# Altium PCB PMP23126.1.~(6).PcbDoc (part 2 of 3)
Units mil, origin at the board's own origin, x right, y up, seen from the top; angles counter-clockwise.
Board outline 1315.03 x 1390.8 mil, 6 copper layers (Top Layer, MidLayer1, MidLayer2, MidLayer3, MidLayer4, Bottom Layer), stack 72.6 mil thick; 49 components, 55 nets, 222 pads, 193 vias.
Unrouted connection lines stored in the file: 15.

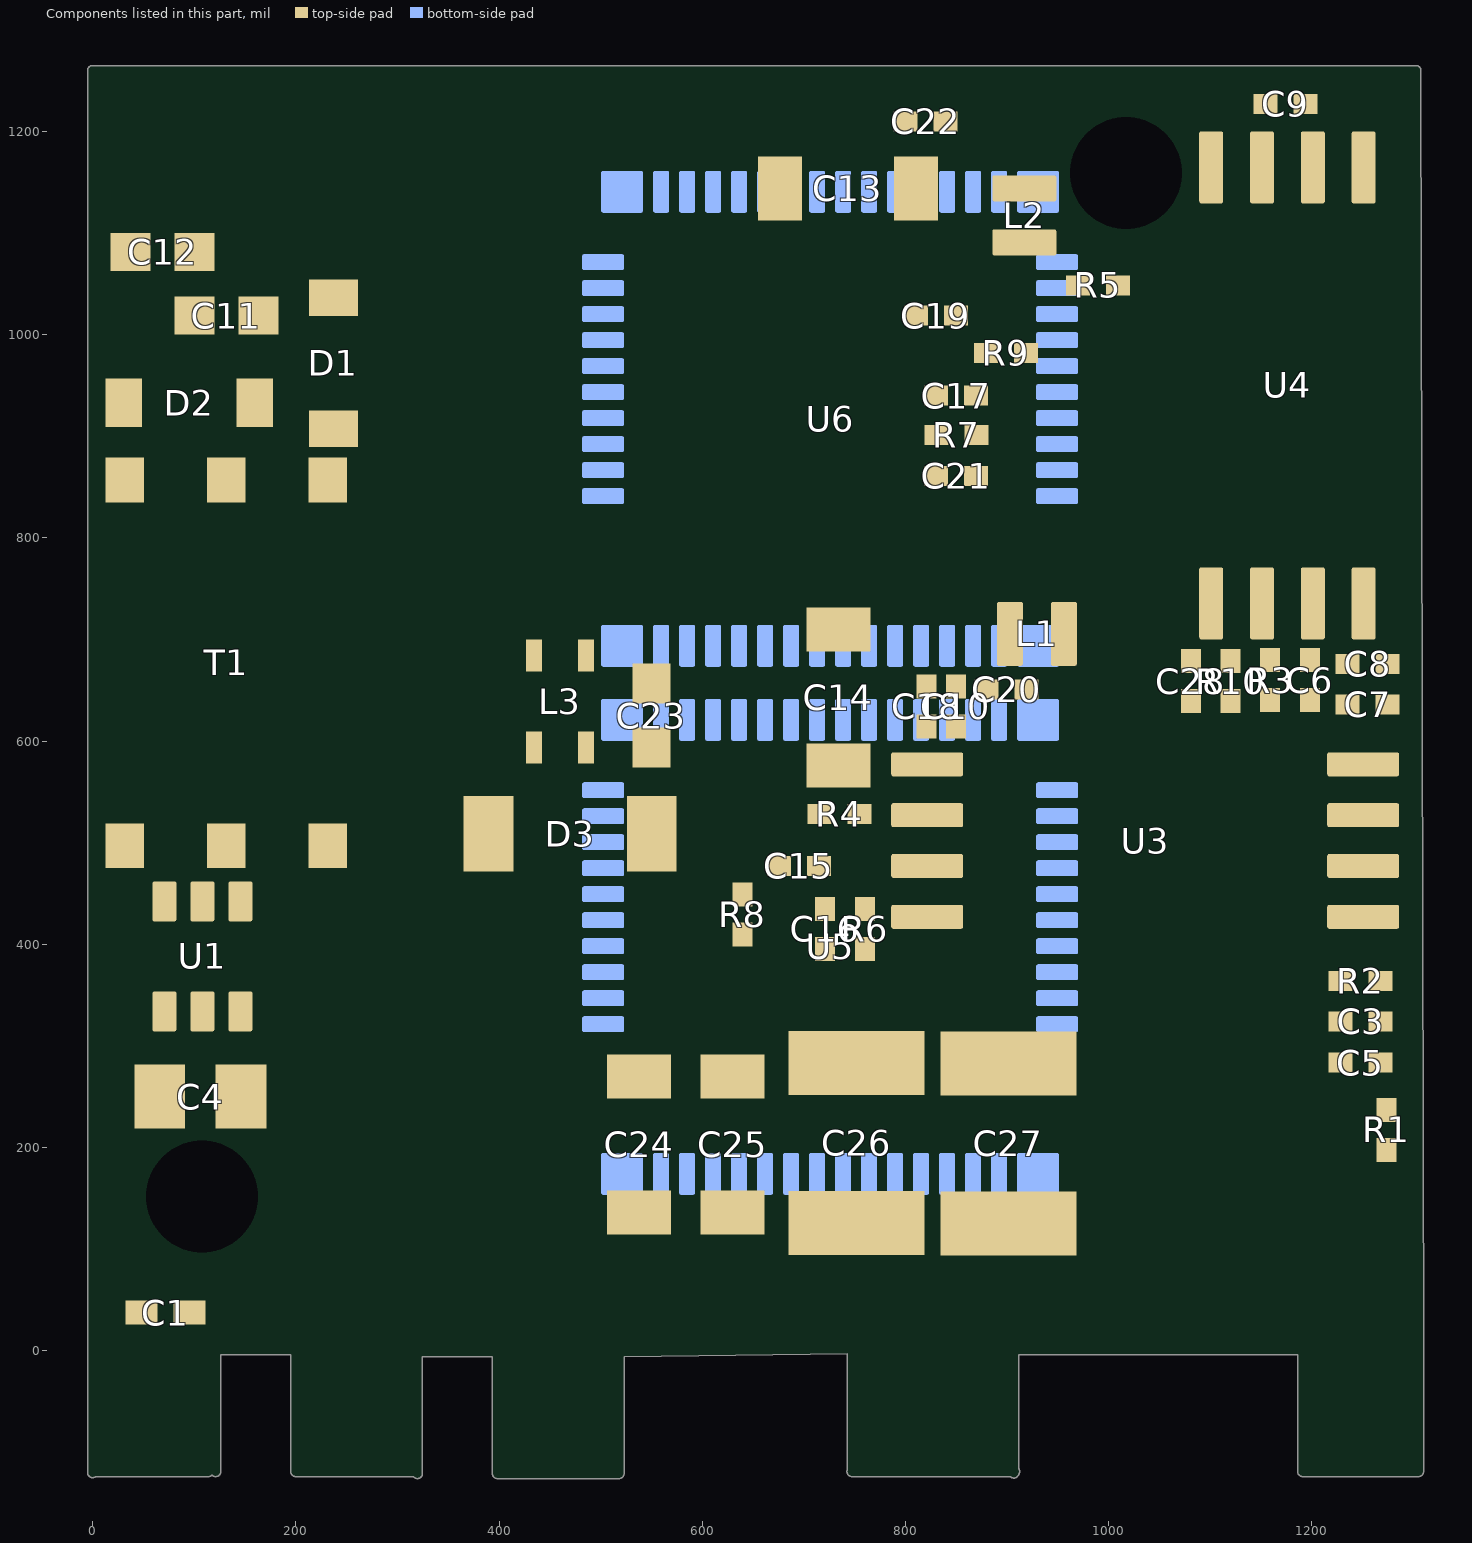
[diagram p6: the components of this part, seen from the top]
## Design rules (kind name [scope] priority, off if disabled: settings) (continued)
PolygonConnect PolygonConnect_45 [All vs IsNamedPolygon('Vbulk1') Or  IsNamedPolygon('TOP_LAYER_VBULK_P104') Or  IsNamedPolygon('SIGNAL_LAYER_1_VBULK1_P106') Or  IsNamedPolygon('Iout_SNS') Or  IsNamedPolygon('SIGNAL_LAYER_2_VBB_P094') Or  IsNamedPolygon('Line') Or  IsNamedPolygon('T200_4') Or  IsNamedPolygon('ZCD') Or  IsNamedPolygon('C108_1') Or  IsNamedPolygon('PGND') Or  IsNamedPolygon('BOTTOM_LAYER_NETC106_2_P030') Or  IsNamedPolygon('5Vp') Or  IsNamedPolygon('C108_1') Or  IsNamedPolygon('Line') Or  IsNamedPolygon('C102_1') Or  IsNamedPolygon('T200_4') Or  IsNamedPolygon('12Vp') Or  IsNamedPolygon('D403_2') Or  IsNamedPolygon('T200_6') Or  IsNamedPolygon('TOP_LAYER_54V1_P046') Or  IsNamedPolygon('TOP_LAYER_54V2_P048') Or  IsNamedPolygon('C108_1') Or  IsNamedPolygon('C108_1') Or  IsNamedPolygon('SWNODE3') Or  IsNamedPolygon('TOP_LAYER_54V2_P048') Or  IsNamedPolygon('PGND') Or  IsNamedPolygon('D403_2') Or  IsNamedPolygon('C108_1') Or  IsNamedPolygon('C108_1') Or  IsNamedPolygon('T200_6') Or  IsNamedPolygon('SGND') Or  IsNamedPolygon('SWNODE') Or  IsNamedPolygon('SGND') Or  IsNamedPolygon('SWNODE3') Or  IsNamedPolygon('BOTTOM_LAYER_54V1_P128') Or  IsNamedPolygon('C102_1') Or  IsNamedPolygon('SWNODE4') Or  IsNamedPolygon('C102_1') Or  IsNamedPolygon('SGND') Or  IsNamedPolygon('C102_1') Or  IsNamedPolygon('SGND') Or  IsNamedPolygon('VSR') Or  IsNamedPolygon('SGND') Or  IsNamedPolygon('SGND') Or  IsNamedPolygon('VSR') Or  IsNamedPolygon('SGND') Or  IsNamedPolygon('SWNODE4') Or  IsNamedPolygon('SGND') Or  IsNamedPolygon('SGND') Or  IsNamedPolygon('Vbulk1') Or  IsNamedPolygon('SGND') Or  IsNamedPolygon('PGND') Or  IsNamedPolygon('SGND') Or  IsNamedPolygon('PGND') Or  IsNamedPolygon('SWNODE3') Or  IsNamedPolygon('ZCD') Or  IsNamedPolygon('VSR') Or  IsNamedPolygon('C102_1') Or  IsNamedPolygon('SWNODE4') Or  IsNamedPolygon('C102_1') Or  IsNamedPolygon('SWNODE4') Or  IsNamedPolygon('SWNODE3') Or  IsNamedPolygon('PGND') Or  IsNamedPolygon('SGND') Or  IsNamedPolygon('D400_2') Or  IsNamedPolygon('SGND') Or  IsNamedPolygon('5Vs') Or  IsNamedPolygon('VBB') Or  IsNamedPolygon('T200_4') Or  IsNamedPolygon('T200_6') Or  IsNamedPolygon('SWNODE4') Or  IsNamedPolygon('LEG4_HS_DRV') Or  IsNamedPolygon('LEG4_LS_DRV') Or  IsNamedPolygon('LEG3_HS_DRV') Or  IsNamedPolygon('BOTTOM_LAYER_54V1_P128') Or  IsNamedPolygon('TOP_LAYER_12VS_P126') Or  IsNamedPolygon('Iout_SNS') Or  IsNamedPolygon('SWNODE3') Or  IsNamedPolygon('SWNODE3') Or  IsNamedPolygon('SWNODE3') Or  IsNamedPolygon('VBB') Or  IsNamedPolygon('Line') Or  IsNamedPolygon('D404_2') Or  IsNamedPolygon('SGND') Or  IsNamedPolygon('VBB') Or  IsNamedPolygon('VBB') Or  IsNamedPolygon('PGND') Or  IsNamedPolygon('PGND') Or  IsNamedPolygon('PGND') Or  IsNamedPolygon('PGND') Or  IsNamedPolygon('PGND') Or  IsNamedPolygon('ZCD') Or  IsNamedPolygon('ZCD') Or  IsNamedPolygon('C412_2') Or  IsNamedPolygon('VBB') Or  IsNamedPolygon('PGND') Or  IsNamedPolygon('PGND') Or  IsNamedPolygon('PGND') Or  IsNamedPolygon('PGND') Or  IsNamedPolygon('PGND') Or  IsNamedPolygon('PGND') Or  IsNamedPolygon('PGND') Or  IsNamedPolygon('VBB') Or  IsNamedPolygon('D404_2') Or  IsNamedPolygon('VBB') Or  IsNamedPolygon('Vbulk1') Or  IsNamedPolygon('Vbulk1') Or  IsNamedPolygon('ZCD') Or  IsNamedPolygon('Neutral') Or  IsNamedPolygon('Neutral') Or  IsNamedPolygon('C106_2') Or  IsNamedPolygon('C106_2') Or  IsNamedPolygon('C106_2') Or  IsNamedPolygon('SWNODE') Or  IsNamedPolygon('Vbulk1') Or  IsNamedPolygon('Earth1') Or  IsNamedPolygon('Earth1') Or  IsNamedPolygon('Earth1') Or  IsNamedPolygon('Earth1') Or  IsNamedPolygon('Earth1') Or  IsNamedPolygon('Earth1') Or  IsNamedPolygon('ZCD') Or  IsNamedPolygon('VBB') Or  IsNamedPolygon('PGND') Or  IsNamedPolygon('D106_1') Or  IsNamedPolygon('PGND') Or  IsNamedPolygon('PGND') Or  IsNamedPolygon('D106_1') Or  IsNamedPolygon('VBB') Or  IsNamedPolygon('D106_1') Or  IsNamedPolygon('PGND')] p15: connectstyle=Direct reliefconductorwidth=10 reliefentries=4 polygonreliefangle="90 Angle" airgapwidth=10
PolygonConnect PolygonConnect_44 [All vs IsNamedPolygon('Earth1') Or  IsNamedPolygon('Vbulk1') Or  IsNamedPolygon('Vbulk1') Or  IsNamedPolygon('VBB') Or  IsNamedPolygon('Vbulk1') Or  IsNamedPolygon('ZCD') Or  IsNamedPolygon('VBB') Or  IsNamedPolygon('PGND') Or  IsNamedPolygon('C412_2') Or  IsNamedPolygon('ZCD') Or  IsNamedPolygon('D106_1') Or  IsNamedPolygon('D106_1') Or  IsNamedPolygon('ZCD') Or  IsNamedPolygon('PGND') Or  IsNamedPolygon('PGND') Or  IsNamedPolygon('ZCD') Or  IsNamedPolygon('VBB') Or  IsNamedPolygon('PGND') Or  IsNamedPolygon('VBB') Or  IsNamedPolygon('PGND') Or  IsNamedPolygon('D106_1') Or  IsNamedPolygon('PGND') Or  IsNamedPolygon('PGND') Or  IsNamedPolygon('PGND') Or  IsNamedPolygon('VBB') Or  IsNamedPolygon('PGND') Or  IsNamedPolygon('PGND') Or  IsNamedPolygon('C102_1') Or  IsNamedPolygon('ZCD') Or  IsNamedPolygon('C102_1') Or  IsNamedPolygon('C102_1') Or  IsNamedPolygon('C102_1') Or  IsNamedPolygon('PGND') Or  IsNamedPolygon('C102_1') Or  IsNamedPolygon('Line') Or  IsNamedPolygon('T200_4') Or  IsNamedPolygon('T200_4') Or  IsNamedPolygon('SIGNAL_LAYER_1_VBULK1_P106') Or  IsNamedPolygon('TOP_LAYER_VBULK_P104') Or  IsNamedPolygon('T200_4') Or  IsNamedPolygon('SGND') Or  IsNamedPolygon('T200_6') Or  IsNamedPolygon('C108_1') Or  IsNamedPolygon('SWNODE3') Or  IsNamedPolygon('SWNODE') Or  IsNamedPolygon('SWNODE3') Or  IsNamedPolygon('LEG3_HS_DRV') Or  IsNamedPolygon('BOTTOM_LAYER_NETC106_2_P030') Or  IsNamedPolygon('C102_1') Or  IsNamedPolygon('SWNODE4') Or  IsNamedPolygon('SIGNAL_LAYER_2_VBB_P094') Or  IsNamedPolygon('SGND') Or  IsNamedPolygon('VSR') Or  IsNamedPolygon('C108_1') Or  IsNamedPolygon('BOTTOM_LAYER_54V1_P128') Or  IsNamedPolygon('TOP_LAYER_54V2_P048') Or  IsNamedPolygon('TOP_LAYER_54V1_P046') Or  IsNamedPolygon('C108_1') Or  IsNamedPolygon('D403_2') Or  IsNamedPolygon('ZCD') Or  IsNamedPolygon('PGND') Or  IsNamedPolygon('SWNODE3') Or  IsNamedPolygon('Line') Or  IsNamedPolygon('D400_2') Or  IsNamedPolygon('SGND') Or  IsNamedPolygon('PGND') Or  IsNamedPolygon('SGND') Or  IsNamedPolygon('LEG4_HS_DRV') Or  IsNamedPolygon('SWNODE3') Or  IsNamedPolygon('5Vs') Or  IsNamedPolygon('SWNODE4') Or  IsNamedPolygon('SGND') Or  IsNamedPolygon('SGND') Or  IsNamedPolygon('C108_1') Or  IsNamedPolygon('5Vp') Or  IsNamedPolygon('12Vp') Or  IsNamedPolygon('Iout_SNS') Or  IsNamedPolygon('D404_2') Or  IsNamedPolygon('SGND') Or  IsNamedPolygon('T200_6') Or  IsNamedPolygon('TOP_LAYER_54V2_P048') Or  IsNamedPolygon('SGND') Or  IsNamedPolygon('SWNODE3') Or  IsNamedPolygon('SWNODE4') Or  IsNamedPolygon('Iout_SNS') Or  IsNamedPolygon('C108_1') Or  IsNamedPolygon('BOTTOM_LAYER_54V1_P128') Or  IsNamedPolygon('SWNODE3') Or  IsNamedPolygon('LEG4_LS_DRV') Or  IsNamedPolygon('SGND') Or  IsNamedPolygon('SWNODE4') Or  IsNamedPolygon('T200_6') Or  IsNamedPolygon('TOP_LAYER_12VS_P126') Or  IsNamedPolygon('Line') Or  IsNamedPolygon('Vbulk1') Or  IsNamedPolygon('SWNODE3') Or  IsNamedPolygon('SGND') Or  IsNamedPolygon('VBB') Or  IsNamedPolygon('SGND') Or  IsNamedPolygon('SGND') Or  IsNamedPolygon('SWNODE4') Or  IsNamedPolygon('PGND') Or  IsNamedPolygon('D403_2') Or  IsNamedPolygon('VSR') Or  IsNamedPolygon('SGND') Or  IsNamedPolygon('SGND') Or  IsNamedPolygon('VBB') Or  IsNamedPolygon('C108_1') Or  IsNamedPolygon('Earth1') Or  IsNamedPolygon('Earth1') Or  IsNamedPolygon('VSR') Or  IsNamedPolygon('C106_2') Or  IsNamedPolygon('Vbulk1') Or  IsNamedPolygon('C106_2') Or  IsNamedPolygon('C106_2') Or  IsNamedPolygon('Earth1') Or  IsNamedPolygon('SWNODE') Or  IsNamedPolygon('Neutral') Or  IsNamedPolygon('Earth1') Or  IsNamedPolygon('Earth1') Or  IsNamedPolygon('Neutral')] p16: connectstyle=Direct reliefconductorwidth=10 reliefentries=4 polygonreliefangle="90 Angle" airgapwidth=10
PolygonConnect PolygonConnect_43 [All vs IsNamedPolygon('SWNODE') Or  IsNamedPolygon('D403_2') Or  IsNamedPolygon('D403_2') Or  IsNamedPolygon('PGND') Or  IsNamedPolygon('BOTTOM_LAYER_NETC106_2_P030') Or  IsNamedPolygon('C102_1') Or  IsNamedPolygon('SGND') Or  IsNamedPolygon('TOP_LAYER_54V1_P046') Or  IsNamedPolygon('TOP_LAYER_54V2_P048') Or  IsNamedPolygon('TOP_LAYER_54V2_P048') Or  IsNamedPolygon('C108_1') Or  IsNamedPolygon('C108_1') Or  IsNamedPolygon('C108_1') Or  IsNamedPolygon('C108_1') Or  IsNamedPolygon('C108_1') Or  IsNamedPolygon('C108_1') Or  IsNamedPolygon('PGND') Or  IsNamedPolygon('ZCD') Or  IsNamedPolygon('Line') Or  IsNamedPolygon('5Vp') Or  IsNamedPolygon('12Vp') Or  IsNamedPolygon('T200_4') Or  IsNamedPolygon('T200_6') Or  IsNamedPolygon('SWNODE3') Or  IsNamedPolygon('T200_4') Or  IsNamedPolygon('T200_6') Or  IsNamedPolygon('SWNODE4') Or  IsNamedPolygon('VSR') Or  IsNamedPolygon('Iout_SNS') Or  IsNamedPolygon('SIGNAL_LAYER_2_VBB_P094') Or  IsNamedPolygon('Vbulk1') Or  IsNamedPolygon('TOP_LAYER_VBULK_P104') Or  IsNamedPolygon('SIGNAL_LAYER_1_VBULK1_P106') Or  IsNamedPolygon('Line') Or  IsNamedPolygon('Line') Or  IsNamedPolygon('D404_2') Or  IsNamedPolygon('VBB') Or  IsNamedPolygon('D400_2') Or  IsNamedPolygon('SGND') Or  IsNamedPolygon('PGND') Or  IsNamedPolygon('TOP_LAYER_12VS_P126') Or  IsNamedPolygon('BOTTOM_LAYER_54V1_P128') Or  IsNamedPolygon('LEG3_HS_DRV') Or  IsNamedPolygon('LEG4_LS_DRV') Or  IsNamedPolygon('LEG4_HS_DRV') Or  IsNamedPolygon('SWNODE4') Or  IsNamedPolygon('SWNODE3') Or  IsNamedPolygon('T200_6') Or  IsNamedPolygon('T200_4') Or  IsNamedPolygon('VBB') Or  IsNamedPolygon('5Vs') Or  IsNamedPolygon('SGND') Or  IsNamedPolygon('Iout_SNS') Or  IsNamedPolygon('SGND') Or  IsNamedPolygon('SWNODE3') Or  IsNamedPolygon('SWNODE3') Or  IsNamedPolygon('SWNODE3') Or  IsNamedPolygon('SWNODE3') Or  IsNamedPolygon('SGND') Or  IsNamedPolygon('SGND') Or  IsNamedPolygon('SGND') Or  IsNamedPolygon('SWNODE4') Or  IsNamedPolygon('SWNODE4') Or  IsNamedPolygon('SWNODE4') Or  IsNamedPolygon('VSR') Or  IsNamedPolygon('SWNODE3') Or  IsNamedPolygon('SGND') Or  IsNamedPolygon('SGND') Or  IsNamedPolygon('SGND') Or  IsNamedPolygon('SGND') Or  IsNamedPolygon('SGND') Or  IsNamedPolygon('SGND') Or  IsNamedPolygon('BOTTOM_LAYER_54V1_P128') Or  IsNamedPolygon('SGND') Or  IsNamedPolygon('VSR') Or  IsNamedPolygon('C102_1') Or  IsNamedPolygon('C102_1') Or  IsNamedPolygon('C102_1') Or  IsNamedPolygon('C102_1') Or  IsNamedPolygon('C102_1') Or  IsNamedPolygon('ZCD') Or  IsNamedPolygon('PGND') Or  IsNamedPolygon('PGND') Or  IsNamedPolygon('Vbulk1') Or  IsNamedPolygon('VBB') Or  IsNamedPolygon('Vbulk1') Or  IsNamedPolygon('Vbulk1') Or  IsNamedPolygon('ZCD') Or  IsNamedPolygon('Neutral') Or  IsNamedPolygon('Neutral') Or  IsNamedPolygon('C106_2') Or  IsNamedPolygon('C106_2') Or  IsNamedPolygon('C106_2') Or  IsNamedPolygon('SWNODE') Or  IsNamedPolygon('Vbulk1') Or  IsNamedPolygon('Earth1') Or  IsNamedPolygon('Earth1') Or  IsNamedPolygon('Earth1') Or  IsNamedPolygon('Earth1') Or  IsNamedPolygon('Earth1') Or  IsNamedPolygon('Earth1') Or  IsNamedPolygon('ZCD') Or  IsNamedPolygon('VBB') Or  IsNamedPolygon('PGND') Or  IsNamedPolygon('D106_1') Or  IsNamedPolygon('PGND') Or  IsNamedPolygon('PGND') Or  IsNamedPolygon('D106_1') Or  IsNamedPolygon('VBB') Or  IsNamedPolygon('D106_1') Or  IsNamedPolygon('PGND') Or  IsNamedPolygon('VBB') Or  IsNamedPolygon('VBB') Or  IsNamedPolygon('PGND') Or  IsNamedPolygon('PGND') Or  IsNamedPolygon('PGND') Or  IsNamedPolygon('PGND') Or  IsNamedPolygon('PGND')] p17: connectstyle=Direct reliefconductorwidth=10 reliefentries=4 polygonreliefangle="90 Angle" airgapwidth=10
PolygonConnect PolygonConnect_42 [All vs IsNamedPolygon('Neutral') Or  IsNamedPolygon('Earth1') Or  IsNamedPolygon('Earth1') Or  IsNamedPolygon('D404_2') Or  IsNamedPolygon('Line') Or  IsNamedPolygon('SIGNAL_LAYER_1_VBULK1_P106') Or  IsNamedPolygon('Line') Or  IsNamedPolygon('C102_1') Or  IsNamedPolygon('SWNODE3') Or  IsNamedPolygon('SWNODE3') Or  IsNamedPolygon('SWNODE') Or  IsNamedPolygon('5Vp') Or  IsNamedPolygon('T200_6') Or  IsNamedPolygon('SWNODE3') Or  IsNamedPolygon('SGND') Or  IsNamedPolygon('SWNODE3') Or  IsNamedPolygon('VSR') Or  IsNamedPolygon('C108_1') Or  IsNamedPolygon('SWNODE3') Or  IsNamedPolygon('TOP_LAYER_12VS_P126') Or  IsNamedPolygon('SGND') Or  IsNamedPolygon('SGND') Or  IsNamedPolygon('SGND') Or  IsNamedPolygon('T200_6') Or  IsNamedPolygon('SWNODE4') Or  IsNamedPolygon('C108_1') Or  IsNamedPolygon('C106_2') Or  IsNamedPolygon('SGND') Or  IsNamedPolygon('Neutral') Or  IsNamedPolygon('SIGNAL_LAYER_2_VBB_P094') Or  IsNamedPolygon('Vbulk1') Or  IsNamedPolygon('SGND') Or  IsNamedPolygon('SGND') Or  IsNamedPolygon('TOP_LAYER_54V1_P046') Or  IsNamedPolygon('TOP_LAYER_54V2_P048') Or  IsNamedPolygon('TOP_LAYER_54V2_P048') Or  IsNamedPolygon('C102_1') Or  IsNamedPolygon('SGND') Or  IsNamedPolygon('T200_4') Or  IsNamedPolygon('12Vp') Or  IsNamedPolygon('SGND') Or  IsNamedPolygon('D400_2') Or  IsNamedPolygon('LEG3_HS_DRV') Or  IsNamedPolygon('LEG4_LS_DRV') Or  IsNamedPolygon('T200_4') Or  IsNamedPolygon('BOTTOM_LAYER_54V1_P128') Or  IsNamedPolygon('SGND') Or  IsNamedPolygon('VBB') Or  IsNamedPolygon('SWNODE4') Or  IsNamedPolygon('SWNODE4') Or  IsNamedPolygon('SWNODE4') Or  IsNamedPolygon('VSR') Or  IsNamedPolygon('Iout_SNS') Or  IsNamedPolygon('VBB') Or  IsNamedPolygon('PGND') Or  IsNamedPolygon('Line') Or  IsNamedPolygon('ZCD') Or  IsNamedPolygon('D403_2') Or  IsNamedPolygon('SWNODE3') Or  IsNamedPolygon('Vbulk1') Or  IsNamedPolygon('ZCD') Or  IsNamedPolygon('LEG4_HS_DRV') Or  IsNamedPolygon('BOTTOM_LAYER_54V1_P128') Or  IsNamedPolygon('VBB') Or  IsNamedPolygon('PGND') Or  IsNamedPolygon('ZCD') Or  IsNamedPolygon('ZCD') Or  IsNamedPolygon('Earth1') Or  IsNamedPolygon('VBB') Or  IsNamedPolygon('PGND') Or  IsNamedPolygon('PGND') Or  IsNamedPolygon('Vbulk1') Or  IsNamedPolygon('SWNODE') Or  IsNamedPolygon('C106_2') Or  IsNamedPolygon('C106_2') Or  IsNamedPolygon('C108_1') Or  IsNamedPolygon('SWNODE3') Or  IsNamedPolygon('SWNODE4') Or  IsNamedPolygon('Vbulk1') Or  IsNamedPolygon('SGND') Or  IsNamedPolygon('C102_1') Or  IsNamedPolygon('BOTTOM_LAYER_NETC106_2_P030') Or  IsNamedPolygon('Earth1') Or  IsNamedPolygon('Earth1') Or  IsNamedPolygon('Vbulk1') Or  IsNamedPolygon('Earth1') Or  IsNamedPolygon('T200_6') Or  IsNamedPolygon('T200_4') Or  IsNamedPolygon('C102_1') Or  IsNamedPolygon('C102_1') Or  IsNamedPolygon('C102_1') Or  IsNamedPolygon('VBB') Or  IsNamedPolygon('5Vs') Or  IsNamedPolygon('SGND') Or  IsNamedPolygon('Iout_SNS') Or  IsNamedPolygon('C108_1') Or  IsNamedPolygon('C108_1') Or  IsNamedPolygon('C108_1') Or  IsNamedPolygon('PGND') Or  IsNamedPolygon('D403_2') Or  IsNamedPolygon('PGND') Or  IsNamedPolygon('SGND') Or  IsNamedPolygon('SGND') Or  IsNamedPolygon('VSR')] p18: connectstyle=Direct reliefconductorwidth=10 reliefentries=4 polygonreliefangle="90 Angle" airgapwidth=10
PolygonConnect PolygonConnect_41 [All vs IsNamedPolygon('VBB') Or  IsNamedPolygon('SWNODE3') Or  IsNamedPolygon('T200_4') Or  IsNamedPolygon('Earth1') Or  IsNamedPolygon('BOTTOM_LAYER_54V1_P128') Or  IsNamedPolygon('SGND') Or  IsNamedPolygon('TOP_LAYER_12VS_P126') Or  IsNamedPolygon('C102_1') Or  IsNamedPolygon('VSR') Or  IsNamedPolygon('Earth1') Or  IsNamedPolygon('Neutral') Or  IsNamedPolygon('Vbulk1') Or  IsNamedPolygon('SWNODE4') Or  IsNamedPolygon('C106_2') Or  IsNamedPolygon('PGND') Or  IsNamedPolygon('SGND') Or  IsNamedPolygon('VBB') Or  IsNamedPolygon('PGND') Or  IsNamedPolygon('LEG4_LS_DRV') Or  IsNamedPolygon('C102_1') Or  IsNamedPolygon('SWNODE4') Or  IsNamedPolygon('C106_2') Or  IsNamedPolygon('Vbulk1') Or  IsNamedPolygon('C102_1') Or  IsNamedPolygon('BOTTOM_LAYER_54V1_P128') Or  IsNamedPolygon('LEG3_HS_DRV') Or  IsNamedPolygon('SGND') Or  IsNamedPolygon('SGND') Or  IsNamedPolygon('Earth1') Or  IsNamedPolygon('SGND') Or  IsNamedPolygon('SGND') Or  IsNamedPolygon('5Vs') Or  IsNamedPolygon('LEG4_HS_DRV') Or  IsNamedPolygon('Earth1') Or  IsNamedPolygon('SGND') Or  IsNamedPolygon('SWNODE3') Or  IsNamedPolygon('Iout_SNS') Or  IsNamedPolygon('ZCD') Or  IsNamedPolygon('Earth1') Or  IsNamedPolygon('VSR') Or  IsNamedPolygon('C102_1') Or  IsNamedPolygon('C102_1') Or  IsNamedPolygon('Vbulk1') Or  IsNamedPolygon('C106_2') Or  IsNamedPolygon('ZCD') Or  IsNamedPolygon('SWNODE3') Or  IsNamedPolygon('SWNODE3') Or  IsNamedPolygon('Vbulk1') Or  IsNamedPolygon('SWNODE4') Or  IsNamedPolygon('Neutral') Or  IsNamedPolygon('SWNODE3') Or  IsNamedPolygon('SWNODE4') Or  IsNamedPolygon('Earth1') Or  IsNamedPolygon('D400_2') Or  IsNamedPolygon('SGND') Or  IsNamedPolygon('SGND') Or  IsNamedPolygon('SGND') Or  IsNamedPolygon('SWNODE') Or  IsNamedPolygon('VSR') Or  IsNamedPolygon('SGND') Or  IsNamedPolygon('SIGNAL_LAYER_1_VBULK1_P106') Or  IsNamedPolygon('SGND') Or  IsNamedPolygon('T200_6') Or  IsNamedPolygon('SWNODE4') Or  IsNamedPolygon('VBB') Or  IsNamedPolygon('T200_6') Or  IsNamedPolygon('Line') Or  IsNamedPolygon('Iout_SNS') Or  IsNamedPolygon('Vbulk1') Or  IsNamedPolygon('VBB') Or  IsNamedPolygon('SIGNAL_LAYER_2_VBB_P094') Or  IsNamedPolygon('SGND') Or  IsNamedPolygon('D404_2') Or  IsNamedPolygon('SWNODE3') Or  IsNamedPolygon('Line') Or  IsNamedPolygon('PGND') Or  IsNamedPolygon('TOP_LAYER_54V2_P048') Or  IsNamedPolygon('TOP_LAYER_54V1_P046') Or  IsNamedPolygon('TOP_LAYER_54V2_P048') Or  IsNamedPolygon('C108_1') Or  IsNamedPolygon('BOTTOM_LAYER_NETC106_2_P030') Or  IsNamedPolygon('D403_2') Or  IsNamedPolygon('T200_4') Or  IsNamedPolygon('Line') Or  IsNamedPolygon('PGND') Or  IsNamedPolygon('SWNODE3') Or  IsNamedPolygon('ZCD') Or  IsNamedPolygon('SWNODE') Or  IsNamedPolygon('D403_2') Or  IsNamedPolygon('C108_1') Or  IsNamedPolygon('C102_1') Or  IsNamedPolygon('C108_1') Or  IsNamedPolygon('PGND') Or  IsNamedPolygon('C108_1') Or  IsNamedPolygon('C108_1') Or  IsNamedPolygon('5Vp') Or  IsNamedPolygon('T200_4') Or  IsNamedPolygon('12Vp') Or  IsNamedPolygon('T200_6') Or  IsNamedPolygon('C108_1') Or  IsNamedPolygon('SGND')] p19: connectstyle=Direct reliefconductorwidth=10 reliefentries=4 polygonreliefangle="90 Angle" airgapwidth=10
PolygonConnect PolygonConnect_40 [All vs IsNamedPolygon('Neutral')] p20: connectstyle=Direct reliefconductorwidth=10 reliefentries=4 polygonreliefangle="90 Angle" airgapwidth=10
PolygonConnect PolygonConnect_39 [All vs IsNamedPolygon('12Vp')] p21: connectstyle=Direct reliefconductorwidth=10 reliefentries=4 polygonreliefangle="90 Angle" airgapwidth=10
PolygonConnect PolygonConnect_38 [All vs IsNamedPolygon('SWNODE') Or  IsNamedPolygon('D403_2') Or  IsNamedPolygon('D403_2') Or  IsNamedPolygon('PGND') Or  IsNamedPolygon('BOTTOM_LAYER_NETC106_2_P030') Or  IsNamedPolygon('C102_1') Or  IsNamedPolygon('SGND') Or  IsNamedPolygon('TOP_LAYER_54V1_P046') Or  IsNamedPolygon('TOP_LAYER_54V2_P048') Or  IsNamedPolygon('TOP_LAYER_54V2_P048') Or  IsNamedPolygon('C108_1') Or  IsNamedPolygon('C108_1') Or  IsNamedPolygon('C108_1') Or  IsNamedPolygon('C108_1') Or  IsNamedPolygon('C108_1') Or  IsNamedPolygon('C108_1') Or  IsNamedPolygon('PGND') Or  IsNamedPolygon('ZCD') Or  IsNamedPolygon('Line') Or  IsNamedPolygon('5Vp') Or  IsNamedPolygon('12Vp') Or  IsNamedPolygon('T200_4') Or  IsNamedPolygon('T200_6') Or  IsNamedPolygon('SWNODE3') Or  IsNamedPolygon('T200_4') Or  IsNamedPolygon('T200_6') Or  IsNamedPolygon('SWNODE4') Or  IsNamedPolygon('VSR') Or  IsNamedPolygon('Iout_SNS') Or  IsNamedPolygon('SIGNAL_LAYER_2_VBB_P094') Or  IsNamedPolygon('Vbulk1') Or  IsNamedPolygon('VBB') Or  IsNamedPolygon('SIGNAL_LAYER_1_VBULK1_P106') Or  IsNamedPolygon('Line') Or  IsNamedPolygon('Line') Or  IsNamedPolygon('Line') Or  IsNamedPolygon('D404_2') Or  IsNamedPolygon('VBB') Or  IsNamedPolygon('D400_2') Or  IsNamedPolygon('SGND') Or  IsNamedPolygon('PGND') Or  IsNamedPolygon('TOP_LAYER_12VS_P126') Or  IsNamedPolygon('BOTTOM_LAYER_54V1_P128') Or  IsNamedPolygon('LEG3_HS_DRV') Or  IsNamedPolygon('LEG4_LS_DRV') Or  IsNamedPolygon('LEG4_HS_DRV') Or  IsNamedPolygon('SWNODE4') Or  IsNamedPolygon('SWNODE3') Or  IsNamedPolygon('T200_6') Or  IsNamedPolygon('T200_4') Or  IsNamedPolygon('VBB') Or  IsNamedPolygon('5Vs') Or  IsNamedPolygon('SGND') Or  IsNamedPolygon('Iout_SNS') Or  IsNamedPolygon('SGND') Or  IsNamedPolygon('SWNODE3') Or  IsNamedPolygon('SWNODE3') Or  IsNamedPolygon('SWNODE3') Or  IsNamedPolygon('SWNODE3') Or  IsNamedPolygon('SGND') Or  IsNamedPolygon('SGND') Or  IsNamedPolygon('SGND') Or  IsNamedPolygon('SWNODE4') Or  IsNamedPolygon('SWNODE4') Or  IsNamedPolygon('SWNODE4') Or  IsNamedPolygon('VSR') Or  IsNamedPolygon('SWNODE3') Or  IsNamedPolygon('SGND') Or  IsNamedPolygon('SGND') Or  IsNamedPolygon('SGND') Or  IsNamedPolygon('SGND') Or  IsNamedPolygon('SGND') Or  IsNamedPolygon('SGND') Or  IsNamedPolygon('BOTTOM_LAYER_54V1_P128') Or  IsNamedPolygon('SGND') Or  IsNamedPolygon('VSR') Or  IsNamedPolygon('C102_1') Or  IsNamedPolygon('C102_1') Or  IsNamedPolygon('C102_1') Or  IsNamedPolygon('C102_1') Or  IsNamedPolygon('C102_1') Or  IsNamedPolygon('ZCD') Or  IsNamedPolygon('PGND') Or  IsNamedPolygon('PGND') Or  IsNamedPolygon('Vbulk1') Or  IsNamedPolygon('VBB') Or  IsNamedPolygon('Vbulk1') Or  IsNamedPolygon('Vbulk1') Or  IsNamedPolygon('ZCD') Or  IsNamedPolygon('Neutral') Or  IsNamedPolygon('Neutral')] p22: connectstyle=Direct reliefconductorwidth=10 reliefentries=4 polygonreliefangle="90 Angle" airgapwidth=10
PolygonConnect PolygonConnect_37 [All vs IsNamedPolygon('SGND') Or  IsNamedPolygon('SWNODE4') Or  IsNamedPolygon('5Vp') Or  IsNamedPolygon('SWNODE4') Or  IsNamedPolygon('VBB') Or  IsNamedPolygon('Line') Or  IsNamedPolygon('SGND') Or  IsNamedPolygon('SIGNAL_LAYER_2_C102_1_P032') Or  IsNamedPolygon('TOP_LAYER_54V2_P048') Or  IsNamedPolygon('ZCD') Or  IsNamedPolygon('PGND') Or  IsNamedPolygon('SIGNAL_LAYER_2_VBB_P094') Or  IsNamedPolygon('Line') Or  IsNamedPolygon('Line') Or  IsNamedPolygon('D404_2') Or  IsNamedPolygon('PGND') Or  IsNamedPolygon('SIGNAL_LAYER_1_ZCD_P108') Or  IsNamedPolygon('SWNODE3') Or  IsNamedPolygon('SIGNAL_LAYER_4_C102_1_P038') Or  IsNamedPolygon('SWNODE3') Or  IsNamedPolygon('LEG4_HS_DRV') Or  IsNamedPolygon('SWNODE4') Or  IsNamedPolygon('5Vs') Or  IsNamedPolygon('VBB') Or  IsNamedPolygon('TOP_LAYER_54V2_P048') Or  IsNamedPolygon('C102_1') Or  IsNamedPolygon('LEG4_LS_DRV') Or  IsNamedPolygon('T200_4') Or  IsNamedPolygon('SWNODE3') Or  IsNamedPolygon('Line') Or  IsNamedPolygon('SGND') Or  IsNamedPolygon('SGND') Or  IsNamedPolygon('SWNODE4') Or  IsNamedPolygon('12Vp') Or  IsNamedPolygon('BOTTOM_LAYER_NETC106_2_P030') Or  IsNamedPolygon('T200_4') Or  IsNamedPolygon('Vbulk1') Or  IsNamedPolygon('C108_1') Or  IsNamedPolygon('BOTTOM_LAYER_54V1_P128') Or  IsNamedPolygon('BOTTOM_LAYER_54V1_P128') Or  IsNamedPolygon('SWNODE') Or  IsNamedPolygon('Iout_SNS') Or  IsNamedPolygon('VSR') Or  IsNamedPolygon('D400_2') Or  IsNamedPolygon('D403_2') Or  IsNamedPolygon('SWNODE3') Or  IsNamedPolygon('T200_6') Or  IsNamedPolygon('SWNODE3') Or  IsNamedPolygon('C108_1') Or  IsNamedPolygon('PGND') Or  IsNamedPolygon('BOTTOM_LAYER_VBULK1_P096') Or  IsNamedPolygon('BOTTOM_LAYER_54V1_P128') Or  IsNamedPolygon('TOP_LAYER_12VS_P126') Or  IsNamedPolygon('SIGNAL_LAYER_1_VBULK1_P106') Or  IsNamedPolygon('T200_4') Or  IsNamedPolygon('SGND') Or  IsNamedPolygon('C108_1') Or  IsNamedPolygon('SWNODE3') Or  IsNamedPolygon('T200_6') Or  IsNamedPolygon('T200_6') Or  IsNamedPolygon('T200_6') Or  IsNamedPolygon('SGND') Or  IsNamedPolygon('C108_1') Or  IsNamedPolygon('SGND') Or  IsNamedPolygon('VBB') Or  IsNamedPolygon('T200_4') Or  IsNamedPolygon('LEG3_HS_DRV') Or  IsNamedPolygon('C108_1') Or  IsNamedPolygon('D403_2') Or  IsNamedPolygon('Iout_SNS') Or  IsNamedPolygon('C108_1') Or  IsNamedPolygon('SWNODE4')] p23: connectstyle=Direct reliefconductorwidth=10 reliefentries=4 polygonreliefangle="90 Angle" airgapwidth=10
PolygonConnect PolygonConnect_36 [All vs IsNamedPolygon('PGND') Or  IsNamedPolygon('BOTTOM_LAYER_54V1_P128') Or  IsNamedPolygon('SGND') Or  IsNamedPolygon('LEG4_LS_DRV') Or  IsNamedPolygon('TOP_LAYER_12VS_P126') Or  IsNamedPolygon('LEG4_HS_DRV') Or  IsNamedPolygon('LEG3_HS_DRV') Or  IsNamedPolygon('SGND') Or  IsNamedPolygon('C108_1') Or  IsNamedPolygon('12Vp') Or  IsNamedPolygon('D403_2') Or  IsNamedPolygon('SIGNAL_LAYER_1_ZCD_P108') Or  IsNamedPolygon('C108_1') Or  IsNamedPolygon('BOTTOM_LAYER_VBULK1_P096') Or  IsNamedPolygon('SWNODE') Or  IsNamedPolygon('T200_4') Or  IsNamedPolygon('D400_2') Or  IsNamedPolygon('C102_1') Or  IsNamedPolygon('Line') Or  IsNamedPolygon('VBB') Or  IsNamedPolygon('Line') Or  IsNamedPolygon('TOP_LAYER_54V2_P048') Or  IsNamedPolygon('BOTTOM_LAYER_NETC106_2_P030') Or  IsNamedPolygon('SIGNAL_LAYER_1_VBULK1_P106') Or  IsNamedPolygon('Line') Or  IsNamedPolygon('5Vp') Or  IsNamedPolygon('BOTTOM_LAYER_54V1_P128') Or  IsNamedPolygon('D404_2') Or  IsNamedPolygon('C108_1') Or  IsNamedPolygon('VSR') Or  IsNamedPolygon('T200_6') Or  IsNamedPolygon('VBB') Or  IsNamedPolygon('C108_1') Or  IsNamedPolygon('SIGNAL_LAYER_2_C102_1_P032') Or  IsNamedPolygon('SGND') Or  IsNamedPolygon('PGND') Or  IsNamedPolygon('SIGNAL_LAYER_4_C102_1_P038') Or  IsNamedPolygon('Vbulk1') Or  IsNamedPolygon('TOP_LAYER_54V2_P048') Or  IsNamedPolygon('Iout_SNS') Or  IsNamedPolygon('PGND') Or  IsNamedPolygon('T200_4') Or  IsNamedPolygon('ZCD') Or  IsNamedPolygon('Line') Or  IsNamedPolygon('C108_1') Or  IsNamedPolygon('D403_2') Or  IsNamedPolygon('SIGNAL_LAYER_2_VBB_P094') Or  IsNamedPolygon('SGND') Or  IsNamedPolygon('C108_1') Or  IsNamedPolygon('SIGNAL_LAYER_1_IOUT_SNS_P044') Or  IsNamedPolygon('BOTTOM_LAYER_54V1_P128') Or  IsNamedPolygon('T200_6')] p24: connectstyle=Direct reliefconductorwidth=10 reliefentries=4 polygonreliefangle="90 Angle" airgapwidth=10
PolygonConnect PolygonConnect_35 [All vs IsNamedPolygon('SWNODE') Or  IsNamedPolygon('D403_2') Or  IsNamedPolygon('D403_2') Or  IsNamedPolygon('PGND') Or  IsNamedPolygon('BOTTOM_LAYER_NETC106_2_P030') Or  IsNamedPolygon('SIGNAL_LAYER_2_C102_1_P032') Or  IsNamedPolygon('C102_1') Or  IsNamedPolygon('SIGNAL_LAYER_4_C102_1_P038') Or  IsNamedPolygon('SGND') Or  IsNamedPolygon('SIGNAL_LAYER_1_IOUT_SNS_P044') Or  IsNamedPolygon('BOTTOM_LAYER_54V1_P128') Or  IsNamedPolygon('TOP_LAYER_54V2_P048') Or  IsNamedPolygon('BOTTOM_LAYER_54V1_P128') Or  IsNamedPolygon('TOP_LAYER_54V2_P048') Or  IsNamedPolygon('C108_1') Or  IsNamedPolygon('C108_1') Or  IsNamedPolygon('C108_1') Or  IsNamedPolygon('C108_1') Or  IsNamedPolygon('C108_1') Or  IsNamedPolygon('C108_1') Or  IsNamedPolygon('PGND') Or  IsNamedPolygon('ZCD') Or  IsNamedPolygon('Line') Or  IsNamedPolygon('5Vp') Or  IsNamedPolygon('12Vp') Or  IsNamedPolygon('T200_4') Or  IsNamedPolygon('T200_6') Or  IsNamedPolygon('SGND') Or  IsNamedPolygon('T200_4') Or  IsNamedPolygon('T200_6') Or  IsNamedPolygon('SGND') Or  IsNamedPolygon('VSR') Or  IsNamedPolygon('Iout_SNS') Or  IsNamedPolygon('SIGNAL_LAYER_2_VBB_P094') Or  IsNamedPolygon('BOTTOM_LAYER_VBULK1_P096') Or  IsNamedPolygon('Vbulk1') Or  IsNamedPolygon('VBB') Or  IsNamedPolygon('SIGNAL_LAYER_1_VBULK1_P106') Or  IsNamedPolygon('SIGNAL_LAYER_1_ZCD_P108') Or  IsNamedPolygon('Line') Or  IsNamedPolygon('Line') Or  IsNamedPolygon('Line') Or  IsNamedPolygon('D404_2') Or  IsNamedPolygon('VBB') Or  IsNamedPolygon('D400_2') Or  IsNamedPolygon('SGND') Or  IsNamedPolygon('PGND') Or  IsNamedPolygon('TOP_LAYER_12VS_P126') Or  IsNamedPolygon('BOTTOM_LAYER_54V1_P128') Or  IsNamedPolygon('LEG3_HS_DRV')] p25: connectstyle=Direct reliefconductorwidth=10 reliefentries=4 polygonreliefangle="90 Angle" airgapwidth=10
PolygonConnect PolygonConnect_34 [All vs IsNamedPolygon('SWNODE') Or  IsNamedPolygon('D403_2') Or  IsNamedPolygon('D403_2') Or  IsNamedPolygon('PGND') Or  IsNamedPolygon('BOTTOM_LAYER_NETC106_2_P030') Or  IsNamedPolygon('SIGNAL_LAYER_2_C102_1_P032') Or  IsNamedPolygon('C102_1') Or  IsNamedPolygon('SIGNAL_LAYER_4_C102_1_P038') Or  IsNamedPolygon('SGND') Or  IsNamedPolygon('SIGNAL_LAYER_1_IOUT_SNS_P044') Or  IsNamedPolygon('BOTTOM_LAYER_54V1_P128') Or  IsNamedPolygon('TOP_LAYER_54V2_P048') Or  IsNamedPolygon('BOTTOM_LAYER_54V1_P128') Or  IsNamedPolygon('TOP_LAYER_54V2_P048') Or  IsNamedPolygon('C108_1') Or  IsNamedPolygon('C108_1') Or  IsNamedPolygon('C108_1') Or  IsNamedPolygon('C108_1') Or  IsNamedPolygon('C108_1') Or  IsNamedPolygon('C108_1') Or  IsNamedPolygon('PGND') Or  IsNamedPolygon('ZCD') Or  IsNamedPolygon('Line') Or  IsNamedPolygon('5Vp') Or  IsNamedPolygon('12Vp') Or  IsNamedPolygon('T200_4') Or  IsNamedPolygon('T200_6') Or  IsNamedPolygon('SGND') Or  IsNamedPolygon('T200_4') Or  IsNamedPolygon('T200_6') Or  IsNamedPolygon('SGND') Or  IsNamedPolygon('VSR') Or  IsNamedPolygon('Iout_SNS') Or  IsNamedPolygon('SIGNAL_LAYER_2_VBB_P094') Or  IsNamedPolygon('BOTTOM_LAYER_VBULK1_P096') Or  IsNamedPolygon('Vbulk1') Or  IsNamedPolygon('VBB') Or  IsNamedPolygon('SIGNAL_LAYER_1_VBULK1_P106') Or  IsNamedPolygon('SIGNAL_LAYER_1_ZCD_P108') Or  IsNamedPolygon('Line') Or  IsNamedPolygon('Line') Or  IsNamedPolygon('Line') Or  IsNamedPolygon('D404_2') Or  IsNamedPolygon('VBB') Or  IsNamedPolygon('D400_2') Or  IsNamedPolygon('SGND')] p26: connectstyle=Direct reliefconductorwidth=10 reliefentries=4 polygonreliefangle="90 Angle" airgapwidth=10
PolygonConnect PolygonConnect_33 [All vs IsNamedPolygon('SIGNAL_LAYER_1_VBULK1_P106')] p27: connectstyle=Direct reliefconductorwidth=10 reliefentries=4 polygonreliefangle="90 Angle" airgapwidth=10
PolygonConnect PolygonConnect_32 [All vs IsNamedPolygon('SIGNAL_LAYER_1_VBULK1_P106')] p28: connectstyle=Direct reliefconductorwidth=10 reliefentries=4 polygonreliefangle="90 Angle" airgapwidth=10
PolygonConnect PolygonConnect_31 [All vs IsNamedPolygon('SIGNAL_LAYER_1_VBULK1_P106')] p29: connectstyle=Direct reliefconductorwidth=10 reliefentries=4 polygonreliefangle="90 Angle" airgapwidth=10
PolygonConnect PolygonConnect_30 [All vs IsNamedPolygon('VBB')] p30: connectstyle=Direct reliefconductorwidth=10 reliefentries=4 polygonreliefangle="90 Angle" airgapwidth=10
PolygonConnect PolygonConnect_29 [All vs IsNamedPolygon('SGND')] p31: connectstyle=Direct reliefconductorwidth=10 reliefentries=4 polygonreliefangle="90 Angle" airgapwidth=10
PolygonConnect PolygonConnect_28 [All vs IsNamedPolygon('Vbulk1')] p32: connectstyle=Direct reliefconductorwidth=10 reliefentries=4 polygonreliefangle="90 Angle" airgapwidth=10
PolygonConnect PolygonConnect_27 [All vs IsNamedPolygon('BOTTOM_LAYER_VBULK1_P096')] p33: connectstyle=Direct reliefconductorwidth=10 reliefentries=4 polygonreliefangle="90 Angle" airgapwidth=10
PolygonConnect PolygonConnect_26 [All vs IsNamedPolygon('SIGNAL_LAYER_2_VBB_P094')] p34: connectstyle=Direct reliefconductorwidth=10 reliefentries=4 polygonreliefangle="90 Angle" airgapwidth=10
PolygonConnect PolygonConnect_25 [All vs IsNamedPolygon('C108_1')] p35: connectstyle=Direct reliefconductorwidth=10 reliefentries=4 polygonreliefangle="90 Angle" airgapwidth=10
PolygonConnect PolygonConnect_24 [All vs IsNamedPolygon('BOTTOM_LAYER_EARTH_P100')] p36: connectstyle=Direct reliefconductorwidth=10 reliefentries=4 polygonreliefangle="90 Angle" airgapwidth=10
PolygonConnect PolygonConnect_23 [All vs IsNamedPolygon('BOTTOM_LAYER_54V1_P128')] p37: connectstyle=Direct reliefconductorwidth=10 reliefentries=4 polygonreliefangle="90 Angle" airgapwidth=10
PolygonConnect PolygonConnect_22 [All vs IsNamedPolygon('BOTTOM_LAYER_VBULK1_P096')] p38: connectstyle=Direct reliefconductorwidth=10 reliefentries=4 polygonreliefangle="90 Angle" airgapwidth=10
PolygonConnect PolygonConnect_21 [All vs IsNamedPolygon('SIGNAL_LAYER_2_VBB_P094')] p39: connectstyle=Direct reliefconductorwidth=10 reliefentries=4 polygonreliefangle="90 Angle" airgapwidth=10
PolygonConnect PolygonConnect_20 [All vs IsNamedPolygon('Iout_SNS')] p40: connectstyle=Direct reliefconductorwidth=10 reliefentries=4 polygonreliefangle="90 Angle" airgapwidth=10
PolygonConnect PolygonConnect_19 [All vs IsNamedPolygon('C108_1') Or  IsNamedPolygon('BOTTOM_LAYER_NETC106_2_P030') Or  IsNamedPolygon('D403_2') Or  IsNamedPolygon('C102_1') Or  IsNamedPolygon('SWNODE') Or  IsNamedPolygon('D403_2') Or  IsNamedPolygon('SIGNAL_LAYER_4_C102_1_P038') Or  IsNamedPolygon('PGND') Or  IsNamedPolygon('SIGNAL_LAYER_2_C102_1_P032') Or  IsNamedPolygon('SIGNAL_LAYER_1_IOUT_SNS_P044') Or  IsNamedPolygon('SGND') Or  IsNamedPolygon('C108_1') Or  IsNamedPolygon('BOTTOM_LAYER_54V1_P128') Or  IsNamedPolygon('C108_1') Or  IsNamedPolygon('C108_1') Or  IsNamedPolygon('TOP_LAYER_54V2_P048') Or  IsNamedPolygon('BOTTOM_LAYER_54V1_P128') Or  IsNamedPolygon('TOP_LAYER_54V2_P048') Or  IsNamedPolygon('C108_1') Or  IsNamedPolygon('C108_1') Or  IsNamedPolygon('12Vp') Or  IsNamedPolygon('5Vp') Or  IsNamedPolygon('Line') Or  IsNamedPolygon('T200_4') Or  IsNamedPolygon('SGND') Or  IsNamedPolygon('VSR') Or  IsNamedPolygon('ZCD') Or  IsNamedPolygon('PGND') Or  IsNamedPolygon('T200_6') Or  IsNamedPolygon('Neutral') Or  IsNamedPolygon('T200_4') Or  IsNamedPolygon('SGND') Or  IsNamedPolygon('T200_6')] p41: connectstyle=Direct reliefconductorwidth=10 reliefentries=4 polygonreliefangle="90 Angle" airgapwidth=10
PolygonConnect PolygonConnect_18 [All vs IsNamedPolygon('SWNODE') Or  IsNamedPolygon('D403_2') Or  IsNamedPolygon('D403_2') Or  IsNamedPolygon('PGND') Or  IsNamedPolygon('BOTTOM_LAYER_NETC106_2_P030') Or  IsNamedPolygon('SIGNAL_LAYER_2_C102_1_P032') Or  IsNamedPolygon('C102_1') Or  IsNamedPolygon('SIGNAL_LAYER_4_C102_1_P038') Or  IsNamedPolygon('SGND') Or  IsNamedPolygon('SIGNAL_LAYER_1_IOUT_SNS_P044') Or  IsNamedPolygon('BOTTOM_LAYER_54V1_P128') Or  IsNamedPolygon('TOP_LAYER_54V2_P048') Or  IsNamedPolygon('BOTTOM_LAYER_54V1_P128') Or  IsNamedPolygon('TOP_LAYER_54V2_P048') Or  IsNamedPolygon('C108_1') Or  IsNamedPolygon('C108_1') Or  IsNamedPolygon('C108_1') Or  IsNamedPolygon('C108_1') Or  IsNamedPolygon('C108_1') Or  IsNamedPolygon('C108_1') Or  IsNamedPolygon('Neutral') Or  IsNamedPolygon('PGND') Or  IsNamedPolygon('ZCD') Or  IsNamedPolygon('Line') Or  IsNamedPolygon('5Vp') Or  IsNamedPolygon('12Vp') Or  IsNamedPolygon('T200_4') Or  IsNamedPolygon('T200_6') Or  IsNamedPolygon('SGND') Or  IsNamedPolygon('T200_4') Or  IsNamedPolygon('T200_6') Or  IsNamedPolygon('SGND')] p42: connectstyle=Direct reliefconductorwidth=10 reliefentries=4 polygonreliefangle="90 Angle" airgapwidth=10
PolygonConnect PolygonConnect_17 [All vs IsNamedPolygon('12Vp') Or  IsNamedPolygon('T200_4') Or  IsNamedPolygon('T200_6') Or  IsNamedPolygon('SGND') Or  IsNamedPolygon('TOP_LAYER_54V2_P048') Or  IsNamedPolygon('SIGNAL_LAYER_1_IOUT_SNS_P044') Or  IsNamedPolygon('BOTTOM_LAYER_54V1_P128') Or  IsNamedPolygon('SGND') Or  IsNamedPolygon('C102_1') Or  IsNamedPolygon('SIGNAL_LAYER_4_C102_1_P038') Or  IsNamedPolygon('Neutral') Or  IsNamedPolygon('C108_1') Or  IsNamedPolygon('C108_1') Or  IsNamedPolygon('C108_1') Or  IsNamedPolygon('BOTTOM_LAYER_54V1_P128') Or  IsNamedPolygon('TOP_LAYER_54V2_P048') Or  IsNamedPolygon('SIGNAL_LAYER_2_C102_1_P032') Or  IsNamedPolygon('SWNODE') Or  IsNamedPolygon('C108_1') Or  IsNamedPolygon('C108_1') Or  IsNamedPolygon('C108_1') Or  IsNamedPolygon('D403_2') Or  IsNamedPolygon('BOTTOM_LAYER_NETC106_2_P030') Or  IsNamedPolygon('PGND') Or  IsNamedPolygon('D403_2') Or  IsNamedPolygon('5Vp') Or  IsNamedPolygon('PGND') Or  IsNamedPolygon('ZCD') Or  IsNamedPolygon('Line')] p43: connectstyle=Direct reliefconductorwidth=10 reliefentries=4 polygonreliefangle="90 Angle" airgapwidth=10
PolygonConnect PolygonConnect_16 [All vs IsNamedPolygon('D403_2') Or  IsNamedPolygon('C102_1') Or  IsNamedPolygon('C108_1') Or  IsNamedPolygon('SWNODE') Or  IsNamedPolygon('BOTTOM_LAYER_54V1_P128') Or  IsNamedPolygon('SGND') Or  IsNamedPolygon('Line') Or  IsNamedPolygon('ZCD') Or  IsNamedPolygon('SIGNAL_LAYER_1_IOUT_SNS_P044') Or  IsNamedPolygon('Neutral') Or  IsNamedPolygon('PGND') Or  IsNamedPolygon('12Vp') Or  IsNamedPolygon('C108_1') Or  IsNamedPolygon('C108_1') Or  IsNamedPolygon('TOP_LAYER_54V2_P048') Or  IsNamedPolygon('C108_1') Or  IsNamedPolygon('TOP_LAYER_54V2_P048') Or  IsNamedPolygon('T200_4') Or  IsNamedPolygon('T200_6') Or  IsNamedPolygon('D403_2') Or  IsNamedPolygon('C108_1') Or  IsNamedPolygon('C108_1') Or  IsNamedPolygon('SIGNAL_LAYER_4_C102_1_P038') Or  IsNamedPolygon('SIGNAL_LAYER_2_C102_1_P032') Or  IsNamedPolygon('PGND') Or  IsNamedPolygon('BOTTOM_LAYER_NETC106_2_P030') Or  IsNamedPolygon('5Vp') Or  IsNamedPolygon('BOTTOM_LAYER_54V1_P128')] p44: connectstyle=Direct reliefconductorwidth=10 reliefentries=4 polygonreliefangle="90 Angle" airgapwidth=10
PolygonConnect PolygonConnect_15 [All vs IsNamedPolygon('SWNODE') Or  IsNamedPolygon('D403_2') Or  IsNamedPolygon('D403_2') Or  IsNamedPolygon('SIGNAL_LAYER_1_PGND_P018') Or  IsNamedPolygon('PGND') Or  IsNamedPolygon('BOTTOM_LAYER_NETC106_2_P030') Or  IsNamedPolygon('SIGNAL_LAYER_2_C102_1_P032') Or  IsNamedPolygon('C102_1') Or  IsNamedPolygon('SIGNAL_LAYER_4_C102_1_P038') Or  IsNamedPolygon('SGND') Or  IsNamedPolygon('SIGNAL_LAYER_1_IOUT_SNS_P044') Or  IsNamedPolygon('BOTTOM_LAYER_54V1_P128') Or  IsNamedPolygon('TOP_LAYER_54V2_P048') Or  IsNamedPolygon('BOTTOM_LAYER_54V1_P128') Or  IsNamedPolygon('TOP_LAYER_54V2_P048') Or  IsNamedPolygon('C108_1') Or  IsNamedPolygon('C108_1') Or  IsNamedPolygon('C108_1') Or  IsNamedPolygon('C108_1') Or  IsNamedPolygon('C108_1') Or  IsNamedPolygon('C108_1') Or  IsNamedPolygon('Neutral') Or  IsNamedPolygon('PGND') Or  IsNamedPolygon('ZCD') Or  IsNamedPolygon('Line') Or  IsNamedPolygon('5Vp') Or  IsNamedPolygon('12Vp')] p45: connectstyle=Direct reliefconductorwidth=10 reliefentries=4 polygonreliefangle="90 Angle" airgapwidth=10
PolygonConnect PolygonConnect_14 [All vs IsNamedPolygon('TOP_LAYER_54V2_P048') Or  IsNamedPolygon('C108_1') Or  IsNamedPolygon('C108_1') Or  IsNamedPolygon('SIGNAL_LAYER_4_C102_1_P038') Or  IsNamedPolygon('C102_1') Or  IsNamedPolygon('SIGNAL_LAYER_2_C102_1_P032') Or  IsNamedPolygon('SIGNAL_LAYER_1_PGND_P018') Or  IsNamedPolygon('SIGNAL_LAYER_1_IOUT_SNS_P044') Or  IsNamedPolygon('SGND') Or  IsNamedPolygon('C108_1') Or  IsNamedPolygon('ZCD') Or  IsNamedPolygon('PGND') Or  IsNamedPolygon('TOP_LAYER_54V2_P048') Or  IsNamedPolygon('BOTTOM_LAYER_NETC106_2_P030') Or  IsNamedPolygon('PGND') Or  IsNamedPolygon('C108_1') Or  IsNamedPolygon('C108_1') Or  IsNamedPolygon('D403_2') Or  IsNamedPolygon('Line') Or  IsNamedPolygon('C108_1') Or  IsNamedPolygon('Neutral') Or  IsNamedPolygon('SWNODE') Or  IsNamedPolygon('D403_2') Or  IsNamedPolygon('BOTTOM_LAYER_54V1_P128') Or  IsNamedPolygon('BOTTOM_LAYER_54V1_P128')] p46: connectstyle=Direct reliefconductorwidth=10 reliefentries=4 polygonreliefangle="90 Angle" airgapwidth=10
PolygonConnect PolygonConnect_13 [All vs IsNamedPolygon('PGND') Or  IsNamedPolygon('D403_2') Or  IsNamedPolygon('SIGNAL_LAYER_1_PGND_P018') Or  IsNamedPolygon('D403_2') Or  IsNamedPolygon('SWNODE') Or  IsNamedPolygon('SGND') Or  IsNamedPolygon('BOTTOM_LAYER_54V1_P128') Or  IsNamedPolygon('C108_1') Or  IsNamedPolygon('SIGNAL_LAYER_4_C102_1_P038') Or  IsNamedPolygon('C108_1') Or  IsNamedPolygon('TOP_LAYER_54V2_P048') Or  IsNamedPolygon('TOP_LAYER_54V2_P048') Or  IsNamedPolygon('C108_1') Or  IsNamedPolygon('C108_1') Or  IsNamedPolygon('C108_1') Or  IsNamedPolygon('BOTTOM_LAYER_NETC106_2_P030') Or  IsNamedPolygon('SIGNAL_LAYER_1_IOUT_SNS_P044') Or  IsNamedPolygon('C108_1') Or  IsNamedPolygon('C102_1') Or  IsNamedPolygon('SIGNAL_LAYER_2_C102_1_P032') Or  IsNamedPolygon('BOTTOM_LAYER_54V1_P128')] p47: connectstyle=Direct reliefconductorwidth=10 reliefentries=4 polygonreliefangle="90 Angle" airgapwidth=10
PolygonConnect PolygonConnect_12 [All vs IsNamedPolygon('TOP_LAYER_54V2_P048')] p48: connectstyle=Direct reliefconductorwidth=10 reliefentries=4 polygonreliefangle="90 Angle" airgapwidth=10
PolygonConnect PolygonConnect_11 [All vs IsNamedPolygon('BOTTOM_LAYER_54V1_P128')] p49: connectstyle=Direct reliefconductorwidth=10 reliefentries=4 polygonreliefangle="90 Angle" airgapwidth=10
PolygonConnect PolygonConnect_10 [All vs IsNamedPolygon('SIGNAL_LAYER_1_IOUT_SNS_P044')] p50: thpad.connectstyle=Direct thpad.reliefconductorwidth=10 thpad.reliefentries=4 thpad.polygonreliefangle="90 Angle" thpad.airgapwidth=10 smdpad.connectstyle=Relief smdpad.reliefconductorwidth=10 smdpad.reliefentries=4 smdpad.polygonreliefangle="90 Angle" smdpad.airgapwidth=10 via.connectstyle=Direct via.reliefconductorwidth=10 via.reliefentries=4 via.polygonreliefangle="90 Angle" via.airgapwidth=10
PolygonConnect PolygonConnect_9 [All vs IsNamedPolygon('SGND')] p51: thpad.connectstyle=Direct thpad.reliefconductorwidth=10 thpad.reliefentries=4 thpad.polygonreliefangle="90 Angle" thpad.airgapwidth=10 smdpad.connectstyle=Relief smdpad.reliefconductorwidth=10 smdpad.reliefentries=4 smdpad.polygonreliefangle="90 Angle" smdpad.airgapwidth=10 via.connectstyle=Direct via.reliefconductorwidth=10 via.reliefentries=4 via.polygonreliefangle="90 Angle" via.airgapwidth=10
PolygonConnect PolygonConnect_8 [All vs IsNamedPolygon('SGND')] p52: thpad.connectstyle=Direct thpad.reliefconductorwidth=10 thpad.reliefentries=4 thpad.polygonreliefangle="90 Angle" thpad.airgapwidth=10 smdpad.connectstyle=Relief smdpad.reliefconductorwidth=10 smdpad.reliefentries=4 smdpad.polygonreliefangle="90 Angle" smdpad.airgapwidth=10 via.connectstyle=Direct via.reliefconductorwidth=10 via.reliefentries=4 via.polygonreliefangle="90 Angle" via.airgapwidth=10
PolygonConnect PolygonConnect_7 [All vs IsNamedPolygon('SGND')] p53: thpad.connectstyle=Relief thpad.reliefconductorwidth=0 thpad.reliefentries=4 thpad.polygonreliefangle="90 Angle" thpad.airgapwidth=0 smdpad.connectstyle=Relief smdpad.reliefconductorwidth=10 smdpad.reliefentries=4 smdpad.polygonreliefangle="90 Angle" smdpad.airgapwidth=10 via.connectstyle=Relief via.reliefconductorwidth=10 via.reliefentries=4 via.polygonreliefangle="90 Angle" via.airgapwidth=10
PolygonConnect PolygonConnect_6 [All vs IsNamedPolygon('SGND')] p54: thpad.connectstyle=Direct thpad.reliefconductorwidth=10 thpad.reliefentries=4 thpad.polygonreliefangle="90 Angle" thpad.airgapwidth=10 smdpad.connectstyle=Relief smdpad.reliefconductorwidth=10 smdpad.reliefentries=4 smdpad.polygonreliefangle="90 Angle" smdpad.airgapwidth=10 via.connectstyle=Relief via.reliefconductorwidth=10 via.reliefentries=4 via.polygonreliefangle="90 Angle" via.airgapwidth=10
PolygonConnect PolygonConnect_5 [All vs IsNamedPolygon('SGND')] p55: thpad.connectstyle=Direct thpad.reliefconductorwidth=10 thpad.reliefentries=4 thpad.polygonreliefangle="90 Angle" thpad.airgapwidth=10 smdpad.connectstyle=Relief smdpad.reliefconductorwidth=10 smdpad.reliefentries=4 smdpad.polygonreliefangle="90 Angle" smdpad.airgapwidth=10 via.connectstyle=Relief via.reliefconductorwidth=10 via.reliefentries=4 via.polygonreliefangle="90 Angle" via.airgapwidth=10
PolygonConnect PolygonConnect_4 [All vs IsNamedPolygon('SIGNAL_LAYER_1_PGND_P018') Or  IsNamedPolygon('SWNODE') Or  IsNamedPolygon('D403_2') Or  IsNamedPolygon('SIGNAL_LAYER_4_C102_1_P038') Or  IsNamedPolygon('D403_2') Or  IsNamedPolygon('BOTTOM_LAYER_NETC106_2_P030') Or  IsNamedPolygon('C102_1') Or  IsNamedPolygon('PGND') Or  IsNamedPolygon('SIGNAL_LAYER_2_C102_1_P032')] p56: connectstyle=Direct reliefconductorwidth=10 reliefentries=4 polygonreliefangle="90 Angle" airgapwidth=10
PolygonConnect PolygonConnect_3 [All vs IsNamedPolygon('SWNODE') Or  IsNamedPolygon('D403_2') Or  IsNamedPolygon('Neutral') Or  IsNamedPolygon('C106_2') Or  IsNamedPolygon('D403_2') Or  IsNamedPolygon('Neutral') Or  IsNamedPolygon('Neutral')] p57: connectstyle=Direct reliefconductorwidth=10 reliefentries=4 polygonreliefangle="90 Angle" airgapwidth=10
PolygonConnect PolygonConnect_2 [All vs IsNamedPolygon('Neutral') Or  IsNamedPolygon('Neutral') Or  IsNamedPolygon('C106_2') Or  IsNamedPolygon('SWNODE') Or  IsNamedPolygon('Neutral')] p58: connectstyle=Direct reliefconductorwidth=10 reliefentries=4 polygonreliefangle="90 Angle" airgapwidth=10
PolygonConnect PolygonConnect_1 [All vs IsNamedPolygon('Neutral') Or  IsNamedPolygon('Neutral')] p59: connectstyle=Direct reliefconductorwidth=10 reliefentries=4 polygonreliefangle="90 Angle" airgapwidth=10
PolygonConnect [All] p60: connectstyle=Direct reliefconductorwidth=10 reliefentries=4 polygonreliefangle="90 Angle" airgapwidth=10
RoutingVias ThermalPadVias [IsVia and InAnyComponent] p1: holewidth=7.87 width=19.68 viastyle="Through Hole" minholewidth=7.87 minwidth=19.68 maxholewidth=12.99 maxwidth=23.62
RoutingVias [All] p2: holewidth=10 width=34 viastyle="Through Hole" minholewidth=7.87 minwidth=19 maxholewidth=40 maxwidth=65
SilkToSilkClearance SilkToSilkClearance_Pb-FreeLogo [(HasFootprint('Pb-Free_Overlay_Medium') OR HasFootprint('Pb-Free_Overlay_Small')) vs (HasFootprint('Pb-Free_Overlay_Medium') OR HasFootprint('Pb-Free_Overlay_Small'))] p1: silktosilkclearance=0
SilkToSilkClearance [All] p2: silktosilkclearance=1
SilkToSolderMaskClearance SilkToComponentPadClearance [(IsPad or IsFill or IsRegion) and InAnycomponent] p1: minsilkscreentomaskgap=1 clearancetoexposedcopper=TRUE
SilkToSolderMaskClearance "Silk to Solder Mask Opening" [All] p2: minsilkscreentomaskgap=1 clearancetoexposedcopper=FALSE
SolderMaskExpansion [All] p1: expansion=1.97 istentingtop=FALSE
Width [All] p1: maxlimit=100 minlimit=6 preferedwidth=10 substack1={A02F224D-4808-492E-A71F-5F5656FBF0D4} substack2={B838D286-A00B-4EE2-88E1-F79279CC64B4} substack3={0D253197-D122-4D2B-9584-B8C12AA3806F} substack4={88BCB183-C685-456E-B90A-365A53404C2C} substack5={4C8C2325-90D5-40B8-8B6B-4F66D44EFE25} substack6={553D66F5-99EF-40B1-BA7C-73E3B04B176F} substack7={FF0C9878-5A48-402E-B013-8E2EEFCEDCCB} substack8={5BB5B65B-6C7F-4868-A6AE-66DD57ADDCBD} substack9={65866CD6-1929-42AF-BAA8-019D5E6BA212} substack10={590F0BEA-1E04-4904-B9C9-D9D160075BC2} substack11={B2AC4F48-1A5F-44D7-A91B-3BAADFDAAED0} substack12={DD3D4156-A54D-4E1F-B7FF-E5EF72C45496} substack13={7CC4AE65-1EB7-43C1-8FCA-3677EE54F737} substack14={E8C37195-128A-4AA0-B681-9B6788FCEC2F} substack15={92E0C252-34CC-4501-B85F-B111C59C3287} substack16={732F7058-E977-446F-8A06-ECA871B5D75E} substack17={990DA1BC-A1DE-47D8-A675-B5A4E74B5332} checkconnectedcopper=TRUE
14 further rules are at their usual default settings.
